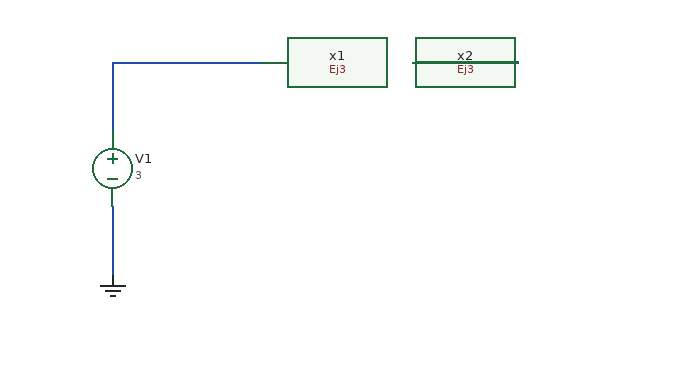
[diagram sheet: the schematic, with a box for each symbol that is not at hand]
v {xschem version=3.0.0 file_version=1.2 }
G {}
K {}
V {}
S {}
E {}
N -205 -265 -205 -210 {}
N -205 -265 -85 -265 {}
N -205 -150 -205 -95 {}
N 35 -265 120 -265 {}
C {NMOS/Ej3.sym} -95 -75 0 0 {name=x1}
C {NMOS/Ej3.sym} 110 -75 0 0 {name=x2}
C {vsource.sym} -205 -180 0 0 {name=V1 value=3}
C {gnd.sym} -205 -95 0 0 {name=l1 lab=GND}
